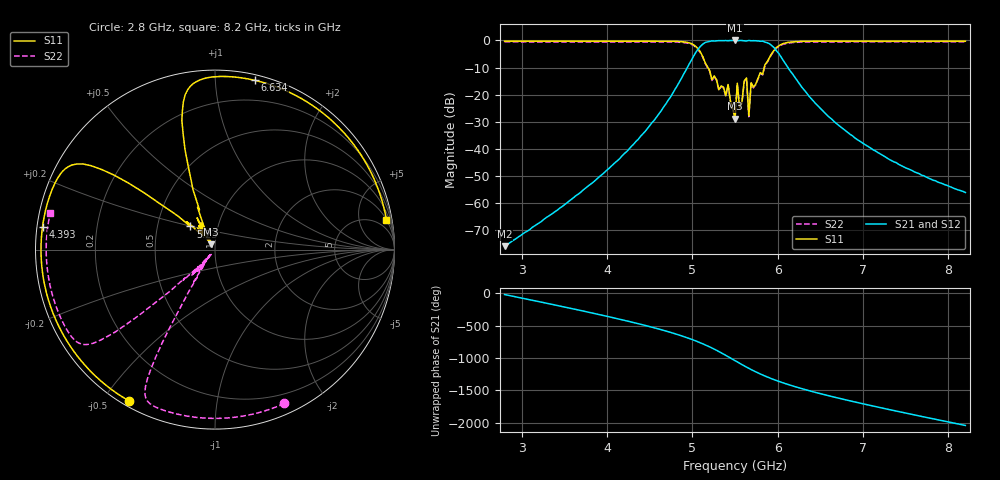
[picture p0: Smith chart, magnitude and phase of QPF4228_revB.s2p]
! written by passband
# GHZ S DB R 50
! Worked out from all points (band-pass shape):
!   201 points, 2.8 GHz to 8.2 GHz, reference 50 ohm
!   highest |S21| = -0.01 dB at 5.5 GHz (marker M1); lowest = -76.0 dB at 2.8 GHz (marker M2)
!   |S21| within 3 dB of the highest: 5.073 GHz to 5.966 GHz (893.3 MHz wide, 16.2 % of centre)
!   lowest |S11| = -28.9 dB at 5.5 GHz (marker M3), VSWR 1.07, Z = 47.9 + j2.81 ohm
!   |S11| at or under -10 dB: 5.182 GHz to 5.843 GHz (660.7 MHz wide, 12 % of centre)
!   |S22| runs from -29.2 to -0.5 dB; largest |S21 - S12| = 0
!   S11 on the Smith chart (normalised r, x): 2.8 GHz: 0.02, -0.58; 4.393 GHz: 0.02, +0.07; 5.23 GHz: 0.74, +0.20; 6.634 GHz: 0.04, +1.26; 8.2 GHz: 2, +11
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2.8  -0.27 -119.6  -75.96 -18.7  -75.96 -18.7  -0.53 -65.7
3.718  -0.27 -158.8  -55.29 87.2  -55.29 87.2  -0.53 -87.2
4.393  -0.27 172.4  -35.40 -118.1  -35.40 -118.1  -0.53 -103.1
4.609  -0.28 163.2  -27.07 167.4  -27.07 167.4  -0.54 -108.1
4.933  -0.67 149.4  -10.53 36.3  -10.53 36.3  -0.94 -115.7
5.068  -3.10 143.6  -3.19 -30.5  -3.19 -30.5  -3.37 -118.9
5.23  -14.53 136.7  -0.17 -125.4  -0.17 -125.4  -14.79 -122.7
5.338  -16.79 132.1  -0.10 161.0  -0.10 161.0  -17.06 -125.2
5.419  -16.25 128.6  -0.11 101.2  -0.11 101.2  -16.51 -127.2
5.5  -28.92 125.1  -0.01 39.4  -0.01 39.4  -29.19 -129.1
5.527  -15.81 124.0  -0.12 18.9  -0.12 18.9  -16.07 -129.7
5.554  -24.85 122.8  -0.02 -1.6  -0.02 -1.6  -25.11 -130.3
5.635  -13.83 119.4  -0.20 -61.0  -0.20 -61.0  -14.10 -132.2
5.662  -27.90 118.2  -0.01 -80.0  -0.01 -80.0  -28.17 -132.9
5.689  -15.58 117.1  -0.13 -98.5  -0.13 -98.5  -15.85 -133.5
5.797  -11.88 112.5  -0.31 -167.2  -0.31 -167.2  -12.14 -136.0
5.932  -4.71 106.7  -1.93 118.3  -1.93 118.3  -4.98 -139.2
6.094  -0.90 99.8  -8.72 42.3  -8.72 42.3  -1.16 -143.0
6.418  -0.29 85.9  -22.35 -83.0  -22.35 -83.0  -0.56 -150.6
6.634  -0.27 76.7  -29.06 -155.5  -29.06 -155.5  -0.54 -155.7
7.309  -0.27 47.9  -43.94 2.2  -43.94 2.2  -0.53 -171.5
8.2  -0.27 9.8  -56.15 117.0  -56.15 117.0  -0.53 167.6
